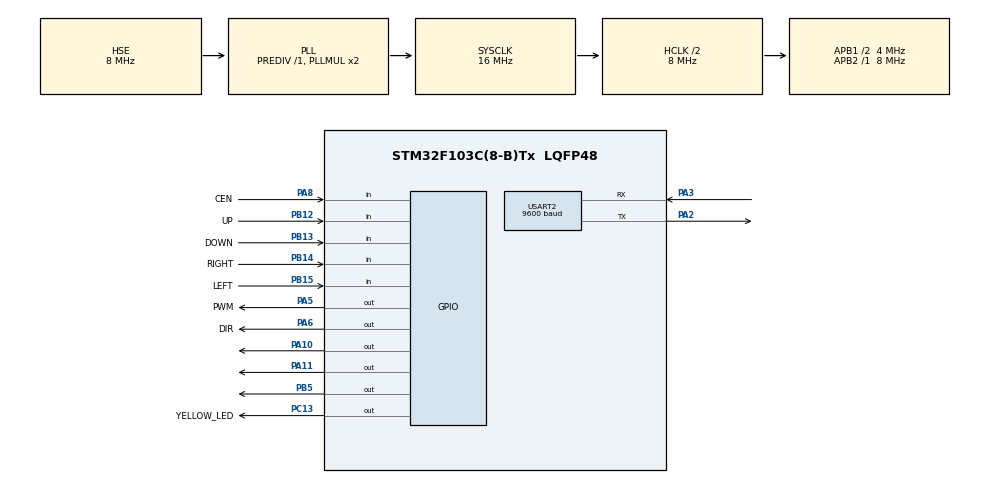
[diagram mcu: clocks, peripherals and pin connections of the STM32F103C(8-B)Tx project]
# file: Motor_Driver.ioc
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Mcu.Family=STM32F1
Mcu.Name=STM32F103C(8-B)Tx
Mcu.Package=LQFP48
NVIC.PriorityGroup=NVIC_PRIORITYGROUP_4
PA10.Signal=GPIO_Output
PA11.Signal=GPIO_Output
PA13.Mode=Serial_Wire
PA13.Signal=SYS_JTMS-SWDIO
PA14.Mode=Serial_Wire
PA14.Signal=SYS_JTCK-SWCLK
PA2.Mode=Asynchronous
PA2.Signal=USART2_TX
PA3.Mode=Asynchronous
PA3.Signal=USART2_RX
PA5.GPIO_Label=PWM
PA5.Signal=GPIO_Output
PA6.GPIO_Label=DIR
PA6.Signal=GPIO_Output
PA8.GPIO_Label=CEN
PA8.Signal=GPIO_Input
PB12.GPIO_Label=UP
PB12.Signal=GPIO_Input
PB13.GPIO_Label=DOWN
PB13.Signal=GPIO_Input
PB14.GPIO_Label=RIGHT
PB14.Signal=GPIO_Input
PB15.GPIO_Label=LEFT
PB15.Signal=GPIO_Input
PB5.Signal=GPIO_Output
PC13-TAMPER-RTC.GPIO_Label=YELLOW_LED
PC13-TAMPER-RTC.Signal=GPIO_Output
PC14-OSC32_IN.Mode=LSE-External-Oscillator
PC14-OSC32_IN.Signal=RCC_OSC32_IN
PC15-OSC32_OUT.Mode=LSE-External-Oscillator
PC15-OSC32_OUT.Signal=RCC_OSC32_OUT
PD0-OSC_IN.Mode=HSE-External-Oscillator
PD0-OSC_IN.Signal=RCC_OSC_IN
PD1-OSC_OUT.Mode=HSE-External-Oscillator
PD1-OSC_OUT.Signal=RCC_OSC_OUT
ProjectManager.HeapSize=0x200
ProjectManager.StackSize=0x400
ProjectManager.TargetToolchain=MDK-ARM V5
RCC.AHBCLKDivider=RCC_SYSCLK_DIV2
RCC.AHBFreq_Value=8000000
RCC.APB1CLKDivider=RCC_HCLK_DIV2
RCC.APB1Freq_Value=4000000
RCC.APB1TimFreq_Value=8000000
RCC.APB2Freq_Value=8000000
RCC.APB2TimFreq_Value=8000000
RCC.HCLKFreq_Value=8000000
RCC.PLLSourceVirtual=RCC_PLLSOURCE_HSE
RCC.SYSCLKFreq_VALUE=16000000
RCC.SYSCLKSource=RCC_SYSCLKSOURCE_PLLCLK
RCC.USBFreq_Value=16000000
USART2.BaudRate=9600
USART2.VirtualMode=VM_ASYNC
board=custom

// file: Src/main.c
/**
  ******************************************************************************
  * @file           : main.c
  * @brief          : Main program body
  ******************************************************************************

  */
#include "main.h"
#include "string.h"
#include "stdio.h"
#include "stm32f1xx_hal.h"
#include "stm32f1xx_hal_lcd1602.h"      //-- Include LCD 16x2 dislplay in Custom Library.
#include "stm32f1xx_hal_delay.h"       //--Include delay in microsecon in Custom Library.

static __IO uint32_t usTicks;

/* USER CODE BEGIN Includes */
char DATA[20];
int s = 0;//--Mang chua du lieu LCD--

/* USER CODE END Includes */
void SysTick_Handler1()
{
	if (usTicks != 0)
	{
		usTicks--;
	}
}
UART_HandleTypeDef huart2;

/* USER CODE BEGIN PV */
/* Private variables ---------------------------------------------------------*/

/* USER CODE END PV */

void SystemClock_Config(void);
static void MX_GPIO_Init(void);
static void MX_USART2_UART_Init(void);

/* USER CODE BEGIN PFP */
/* Private function prototypes -----------------------------------------------*/
#ifdef __GNUC__
  /* With GCC/RAISONANCE, small printf (option LD Linker->Libraries->Small printf
     set to 'Yes') calls __io_putchar() */
  #define PUTCHAR_PROTOTYPE int __io_putchar(int ch)
#else
  #define PUTCHAR_PROTOTYPE int fputc(int ch, FILE *f)
  #define GETCHAR_PROTOTYPE int fgetc(FILE *f)
#endif /* __GNUC__ */
	PUTCHAR_PROTOTYPE
{
  /* Place your implementation of fputc here */
  /* e.g. write a character to the USART */
	HAL_UART_Transmit(&huart2, (uint8_t*)&ch,1,100);

  /* Loop until the end of transmission */

  return ch;
}
/* USER CODE END PFP */

int main(void)
{

  /* MCU Configuration----------------------------------------------------------*/

  /* Reset of all peripherals, Initializes the Flash interface and the Systick. */
  HAL_Init();

  /* Configure the system clock */
  SystemClock_Config();

  /* Initialize all configured peripherals */
  MX_GPIO_Init();
  MX_USART2_UART_Init();

	HAL_GPIO_WritePin(GPIOA,DIR_Pin,GPIO_PIN_SET);     //--Set clockwise of motor.
	//-----
	LCD_Init();
  LCD_Clear();
                                    //--Set LCD display initial.

  LCD_Display_Inital();

  while (1)
  {

  }

}

void SystemClock_Config(void)
{

  RCC_OscInitTypeDef RCC_OscInitStruct;
  RCC_ClkInitTypeDef RCC_ClkInitStruct;

    /**Initializes the CPU, AHB and APB busses clocks
    */
  RCC_OscInitStruct.OscillatorType = RCC_OSCILLATORTYPE_HSE;
  RCC_OscInitStruct.HSEState = RCC_HSE_ON;
  RCC_OscInitStruct.HSEPredivValue = RCC_HSE_PREDIV_DIV1;
  RCC_OscInitStruct.HSIState = RCC_HSI_ON;
  RCC_OscInitStruct.PLL.PLLState = RCC_PLL_ON;
  RCC_OscInitStruct.PLL.PLLSource = RCC_PLLSOURCE_HSE;
  RCC_OscInitStruct.PLL.PLLMUL = RCC_PLL_MUL2;
  if (HAL_RCC_OscConfig(&RCC_OscInitStruct) != HAL_OK)
  {
    _Error_Handler(__FILE__, __LINE__);
  }

    /**Initializes the CPU, AHB and APB busses clocks
    */
  RCC_ClkInitStruct.ClockType = RCC_CLOCKTYPE_HCLK|RCC_CLOCKTYPE_SYSCLK
                              |RCC_CLOCKTYPE_PCLK1|RCC_CLOCKTYPE_PCLK2;
  RCC_ClkInitStruct.SYSCLKSource = RCC_SYSCLKSOURCE_PLLCLK;
  RCC_ClkInitStruct.AHBCLKDivider = RCC_SYSCLK_DIV2;
  RCC_ClkInitStruct.APB1CLKDivider = RCC_HCLK_DIV2;
  RCC_ClkInitStruct.APB2CLKDivider = RCC_HCLK_DIV1;

  if (HAL_RCC_ClockConfig(&RCC_ClkInitStruct, FLASH_LATENCY_0) != HAL_OK)
  {
    _Error_Handler(__FILE__, __LINE__);
  }

    /**Configure the Systick interrupt time
    */
  HAL_SYSTICK_Config(HAL_RCC_GetHCLKFreq()/1000);

    /**Configure the Systick
    */
  HAL_SYSTICK_CLKSourceConfig(SYSTICK_CLKSOURCE_HCLK);

  /* SysTick_IRQn interrupt configuration */
  HAL_NVIC_SetPriority(SysTick_IRQn, 0, 0);
}

/* USART2 init function */
static void MX_USART2_UART_Init(void)
{

  huart2.Instance = USART2;
  huart2.Init.BaudRate = 9600;
  huart2.Init.WordLength = UART_WORDLENGTH_8B;
  huart2.Init.StopBits = UART_STOPBITS_1;
  huart2.Init.Parity = UART_PARITY_NONE;
  huart2.Init.Mode = UART_MODE_TX_RX;
  huart2.Init.HwFlowCtl = UART_HWCONTROL_NONE;
  huart2.Init.OverSampling = UART_OVERSAMPLING_16;
  if (HAL_UART_Init(&huart2) != HAL_OK)
  {
    _Error_Handler(__FILE__, __LINE__);
  }

}

/** Configure pins as
        * Analog
        * Input
        * Output
        * EVENT_OUT
        * EXTI
*/
static void MX_GPIO_Init(void)
{

  GPIO_InitTypeDef GPIO_InitStruct;

  /* GPIO Ports Clock Enable */
  __HAL_RCC_GPIOC_CLK_ENABLE();
  __HAL_RCC_GPIOD_CLK_ENABLE();
  __HAL_RCC_GPIOA_CLK_ENABLE();
  __HAL_RCC_GPIOB_CLK_ENABLE();

  /*Configure GPIO pin Output Level */
  HAL_GPIO_WritePin(YELLOW_LED_GPIO_Port, YELLOW_LED_Pin, GPIO_PIN_RESET);

  /*Configure GPIO pin Output Level */
  HAL_GPIO_WritePin(GPIOA, PWM_Pin|DIR_Pin|GPIO_PIN_10|GPIO_PIN_11, GPIO_PIN_RESET);

  /*Configure GPIO pin Output Level */
  HAL_GPIO_WritePin(GPIOB, GPIO_PIN_5, GPIO_PIN_RESET);

  /*Configure GPIO pin : YELLOW_LED_Pin */
  GPIO_InitStruct.Pin = YELLOW_LED_Pin;
  GPIO_InitStruct.Mode = GPIO_MODE_OUTPUT_PP;
  GPIO_InitStruct.Pull = GPIO_NOPULL;
  GPIO_InitStruct.Speed = GPIO_SPEED_FREQ_LOW;
  HAL_GPIO_Init(YELLOW_LED_GPIO_Port, &GPIO_InitStruct);

  /*Configure GPIO pins : PWM_Pin DIR_Pin PA10 PA11 */
  GPIO_InitStruct.Pin = PWM_Pin|DIR_Pin|GPIO_PIN_9|GPIO_PIN_10|GPIO_PIN_11|GPIO_PIN_0|GPIO_PIN_1|GPIO_PIN_2|GPIO_PIN_3|GPIO_PIN_4|GPIO_PIN_7;
  GPIO_InitStruct.Mode = GPIO_MODE_OUTPUT_PP;
  GPIO_InitStruct.Pull = GPIO_NOPULL;
  GPIO_InitStruct.Speed = GPIO_SPEED_FREQ_LOW;
  HAL_GPIO_Init(GPIOA, &GPIO_InitStruct);

  /*Configure GPIO pins : UP_Pin DOWN_Pin RIGHT_Pin LEFT_Pin */
  GPIO_InitStruct.Pin = UP_Pin|DOWN_Pin|RIGHT_Pin|LEFT_Pin;
  GPIO_InitStruct.Mode = GPIO_MODE_INPUT;
  GPIO_InitStruct.Pull = GPIO_NOPULL;
  HAL_GPIO_Init(GPIOB, &GPIO_InitStruct);

  /*Configure GPIO pin : CEN_Pin */
  GPIO_InitStruct.Pin = CEN_Pin;
  GPIO_InitStruct.Mode = GPIO_MODE_INPUT;
  GPIO_InitStruct.Pull = GPIO_NOPULL;
  HAL_GPIO_Init(CEN_GPIO_Port, &GPIO_InitStruct);

  /*Configure GPIO pin : PB5 */
  GPIO_InitStruct.Pin = GPIO_PIN_5;
  GPIO_InitStruct.Mode = GPIO_MODE_OUTPUT_PP;
  GPIO_InitStruct.Pull = GPIO_NOPULL;
  GPIO_InitStruct.Speed = GPIO_SPEED_FREQ_LOW;
  HAL_GPIO_Init(GPIOB, &GPIO_InitStruct);

	  /*Configure GPIO pin : PB0 */
//  GPIO_InitStruct.Pin = GPIO_PIN_0;
//  GPIO_InitStruct.Mode = GPIO_MODE_INPUT;
//  GPIO_InitStruct.Pull = GPIO_NOPULL;
//  GPIO_InitStruct.Speed = GPIO_SPEED_FREQ_LOW;
//  HAL_GPIO_Init(GPIOB, &GPIO_InitStruct);

}

//----Custom Function-----

void _Error_Handler(char *file, int line)
{
  while(1)
  {
  }
}

/************************ (C) COPYRIGHT STMicroelectronics *****END OF FILE****/
